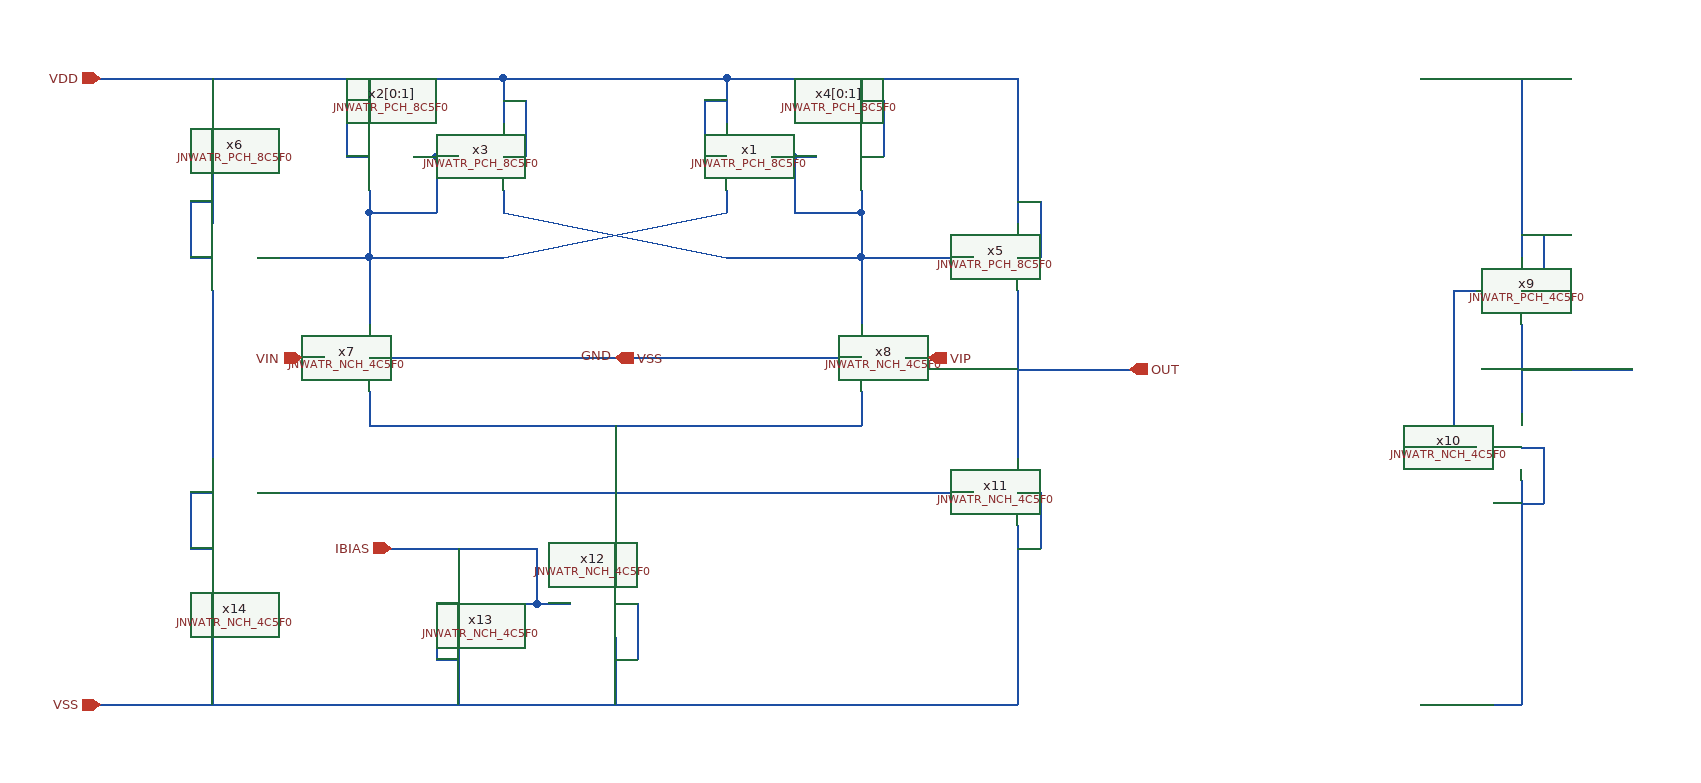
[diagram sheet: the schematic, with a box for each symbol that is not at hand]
v {xschem version=3.4.6 file_version=1.2}
G {}
K {}
V {}
S {}
E {}
N -100 -560 -100 -520 {lab=VDD}
N -100 -560 100 -560 {lab=VDD}
N 100 -560 100 -520 {lab=VDD}
N -460 -560 -100 -560 {lab=VDD}
N 100 -560 340 -560 {lab=VDD}
N 220 -560 220 -520 {lab=VDD}
N -220 -560 -220 -520 {lab=VDD}
N -240 -490 -220 -490 {lab=VDD}
N -100 -490 -80 -490 {lab=VDD}
N 80 -490 100 -490 {lab=VDD}
N 220 -490 240 -490 {lab=VDD}
N -180 -490 -160 -490 {lab=#net1}
N -160 -490 -140 -490 {lab=#net1}
N 140 -490 160 -490 {lab=#net2}
N 160 -490 180 -490 {lab=#net2}
N 220 -460 220 -440 {lab=#net2}
N 160 -440 220 -440 {lab=#net2}
N 160 -490 160 -440 {lab=#net2}
N -220 -460 -220 -440 {lab=#net1}
N -220 -440 -160 -440 {lab=#net1}
N -160 -490 -160 -440 {lab=#net1}
N -100 -460 -100 -440 {lab=#net2}
N 100 -460 100 -440 {lab=#net1}
N -100 -400 100 -440 {lab=#net1}
N -100 -440 100 -400 {lab=#net2}
N 100 -400 220 -400 {lab=#net2}
N 220 -440 220 -400 {lab=#net2}
N -220 -400 -100 -400 {lab=#net1}
N -220 -440 -220 -400 {lab=#net1}
N 340 -560 360 -560 {lab=VDD}
N 360 -560 360 -520 {lab=VDD}
N 360 -520 360 -430 {lab=VDD}
N 360 -400 380 -400 {lab=VDD}
N 380 -450 380 -400 {lab=VDD}
N 360 -450 380 -450 {lab=VDD}
N 220 -400 320 -400 {lab=#net2}
N 240 -540 240 -490 {lab=VDD}
N 80 -540 80 -490 {lab=VDD}
N 80 -540 100 -540 {lab=VDD}
N 220 -540 240 -540 {lab=VDD}
N -80 -540 -80 -490 {lab=VDD}
N -100 -540 -80 -540 {lab=VDD}
N -240 -540 -240 -490 {lab=VDD}
N -240 -540 -220 -540 {lab=VDD}
N -360 -560 -360 -430 {lab=VDD}
N -320 -400 -220 -400 {lab=#net1}
N -380 -400 -360 -400 {lab=VDD}
N -380 -450 -380 -400 {lab=VDD}
N -380 -450 -360 -450 {lab=VDD}
N -220 -400 -220 -350 {lab=#net1}
N -220 -350 -220 -340 {lab=#net1}
N 220 -400 220 -340 {lab=#net2}
N 220 -280 220 -260 {lab=#net3}
N -220 -280 -220 -260 {lab=#net3}
N 0 -220 -0 -200 {lab=#net3}
N 0 -200 0 -120 {lab=#net3}
N -220 -250 220 -250 {lab=#net3}
N -220 -260 -220 -250 {lab=#net3}
N 0 -250 -0 -220 {lab=#net3}
N 360 -370 360 -220 {lab=OUT}
N 220 -260 220 -250 {lab=#net3}
N 260 -310 280 -310 {lab=VIP}
N -280 -310 -260 -310 {lab=VIN}
N -220 -310 -200 -310 {lab=GND}
N 200 -310 220 -310 {lab=GND}
N -320 -190 320 -190 {lab=#net4}
N -360 -370 -360 -220 {lab=#net5}
N 360 -160 360 0 {lab=VSS}
N -460 0 360 0 {lab=VSS}
N -360 -160 -360 0 {lab=VSS}
N -200 -310 200 -310 {lab=GND}
N 0 -60 0 0 {lab=VSS}
N 360 -190 380 -190 {lab=VSS}
N 380 -190 380 -140 {lab=VSS}
N 360 -140 380 -140 {lab=VSS}
N -380 -190 -360 -190 {lab=VSS}
N -380 -190 -380 -140 {lab=VSS}
N -380 -140 -360 -140 {lab=VSS}
N 0 -90 20 -90 {lab=VSS}
N 20 -90 20 -40 {lab=VSS}
N 0 -40 20 -40 {lab=VSS}
N 360 -300 420 -300 {lab=OUT}
N 420 -300 460 -300 {lab=OUT}
N 750 -230 770 -230 {lab=#net6}
N 750 -370 770 -370 {lab=#net6}
N 750 -370 750 -230 {lab=#net6}
N 810 -340 810 -260 {lab=#net7}
N 810 -560 810 -400 {lab=#net8}
N 810 -370 830 -370 {lab=#net8}
N 830 -420 830 -370 {lab=#net8}
N 810 -420 830 -420 {lab=#net8}
N 810 -200 810 0 {lab=#net9}
N 810 -230 830 -230 {lab=#net9}
N 830 -230 830 -180 {lab=#net9}
N 810 -180 830 -180 {lab=#net9}
N 810 -300 910 -300 {lab=#net7}
N -70 -90 -40 -90 {lab=IBIAS}
N -100 -90 -70 -90 {lab=IBIAS}
N -70 -140 -70 -90 {lab=IBIAS}
N -140 -140 -140 -120 {lab=IBIAS}
N -200 -140 -70 -140 {lab=IBIAS}
N -140 -60 -140 0 {lab=VSS}
N -160 -90 -140 -90 {lab=VSS}
N -160 -90 -160 -40 {lab=VSS}
N -160 -40 -140 -40 {lab=VSS}
N 720 -560 810 -560 {lab=#net8}
N 720 0 810 -0 {lab=#net9}
C {JNW_ATR_SKY130A/JNWATR_PCH_8C5F0.sym} -140 -490 0 0 {name=x3 }
C {JNW_ATR_SKY130A/JNWATR_PCH_8C5F0.sym} 140 -490 0 1 {name=x1 }
C {JNW_ATR_SKY130A/JNWATR_PCH_8C5F0.sym} -180 -490 0 1 {name=x2[0:1]}
C {JNW_ATR_SKY130A/JNWATR_PCH_8C5F0.sym} 180 -490 0 0 {name=x4[0:1]}
C {JNW_ATR_SKY130A/JNWATR_PCH_8C5F0.sym} 320 -400 0 0 {name=x5 }
C {JNW_ATR_SKY130A/JNWATR_PCH_8C5F0.sym} -320 -400 0 1 {name=x6 }
C {JNW_ATR_SKY130A/JNWATR_NCH_4C5F0.sym} -260 -310 0 0 {name=x7 }
C {JNW_ATR_SKY130A/JNWATR_NCH_4C5F0.sym} 260 -310 0 1 {name=x8 }
C {JNW_ATR_SKY130A/JNWATR_NCH_4C5F0.sym} -40 -90 0 0 {name=x12}
C {JNW_ATR_SKY130A/JNWATR_NCH_4C5F0.sym} 320 -190 0 0 {name=x11}
C {JNW_ATR_SKY130A/JNWATR_NCH_4C5F0.sym} -320 -190 0 1 {name=x14}
C {devices/lab_wire.sym} 0 -310 2 1 {name=p1 sig_type=std_logic lab=GND}
C {JNW_ATR_SKY130A/JNWATR_PCH_4C5F0.sym} 770 -370 0 0 {name=x9 }
C {JNW_ATR_SKY130A/JNWATR_NCH_4C5F0.sym} 770 -230 0 0 {name=x10}
C {devices/ipin.sym} -460 -560 0 0 {name=p2 lab=VDD}
C {devices/ipin.sym} -460 0 0 0 {name=p3 lab=VSS
}
C {devices/ipin.sym} -280 -310 0 0 {name=p4 lab=VIN}
C {devices/ipin.sym} 280 -310 0 1 {name=p5 lab=VIP}
C {devices/ipin.sym} 0 -310 3 1 {name=p8 lab=VSS
}
C {JNW_ATR_SKY130A/JNWATR_NCH_4C5F0.sym} -100 -90 0 1 {name=x13}
C {devices/ipin.sym} -200 -140 0 0 {name=p6 lab=IBIAS
}
C {devices/opin.sym} 460 -300 0 0 {name=p9 lab=OUT}
